VERSION 5.8 ;
BUSBITCHARS "[]" ;
DIVIDERCHAR "/" ;
UNITS
    DATABASE MICRONS 1000 ;
END UNITS

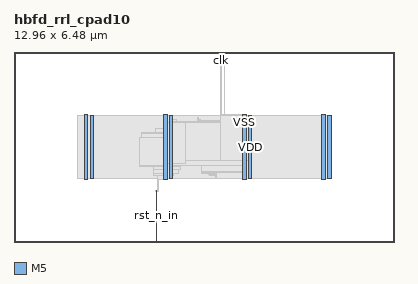
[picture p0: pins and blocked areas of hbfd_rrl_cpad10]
MACRO hbfd_rrl_cpad10
  FOREIGN hbfd_rrl_cpad10 0 0 ;
  CLASS BLOCK ;
  SIZE 12.96 BY 6.48 ;
  PIN clk
    DIRECTION INPUT ;
    USE SIGNAL ;
    PORT
      LAYER M5 ;
        RECT  7.056 6.396 7.08 6.48 ;
    END
  END clk
  PIN rst_n
    DIRECTION OUTPUT ;
    USE SIGNAL ;
    PORT
      LAYER M5 ;
        RECT  7.152 6.396 7.176 6.48 ;
    END
  END rst_n
  PIN rst_n_in
    DIRECTION INPUT ;
    USE SIGNAL ;
    PORT
      LAYER M5 ;
        RECT  4.848 0 4.872 0.084 ;
    END
    PORT
      LAYER M5 ;
        RECT  4.848 0.016 4.872 1.763 ;
    END
  END rst_n_in
  PIN VDD
    DIRECTION INOUT ;
    USE POWER ;
    PORT
      LAYER M5 ;
        RECT  10.692 2.151 10.812 4.329 ;
        RECT  7.992 2.151 8.112 4.329 ;
        RECT  5.292 2.151 5.412 4.329 ;
        RECT  2.592 2.151 2.712 4.329 ;
    END
  END VDD
  PIN VSS
    DIRECTION INOUT ;
    USE GROUND ;
    PORT
      LAYER M5 ;
        RECT  10.5 2.137 10.62 4.343 ;
        RECT  7.8 2.137 7.92 4.343 ;
        RECT  5.1 2.137 5.22 4.343 ;
        RECT  2.4 2.137 2.52 4.343 ;
    END
  END VSS
  # OT_OBS_CLOSED layer=M5 d_um=1.536 added=1
  OBS
    LAYER RVTN ;
     RECT  2.16 2.16 10.8 2.295 ;
     RECT  2.16 2.565 10.8 2.835 ;
     RECT  2.16 3.105 10.8 3.375 ;
     RECT  2.16 3.645 10.8 3.915 ;
     RECT  2.16 4.185 10.8 4.32 ;
    LAYER RVTP ;
     RECT  2.16 2.295 10.8 2.565 ;
     RECT  2.16 2.835 10.8 3.105 ;
     RECT  2.16 3.375 10.8 3.645 ;
     RECT  2.16 3.915 10.8 4.185 ;
    LAYER M1 ;
     RECT  2.16 2.151 10.8 4.329 ;
    LAYER M2 ;
     RECT  2.16 2.151 10.8 4.329 ;
     RECT  10.8 2.421 10.812 4.059 ;
    LAYER M3 ;
     RECT  4.896 1.723 4.914 2.143 ;
     RECT  4.896 2.143 5.205 2.263 ;
     RECT  6.876 2.191 6.894 2.263 ;
     RECT  6.66 2.263 6.894 2.299 ;
     RECT  4.752 2.263 5.454 2.335 ;
     RECT  6.624 2.299 6.894 2.335 ;
     RECT  6.408 2.335 6.894 2.371 ;
     RECT  7.815 2.143 7.905 2.371 ;
     RECT  2.415 2.143 2.505 2.413 ;
     RECT  6.408 2.371 7.905 2.413 ;
     RECT  10.515 2.143 10.605 2.413 ;
     RECT  4.752 2.335 5.598 2.461 ;
     RECT  4.752 2.461 5.67 2.569 ;
     RECT  4.284 2.569 5.67 2.605 ;
     RECT  6.408 2.413 8.097 2.605 ;
     RECT  4.284 2.605 8.097 3.569 ;
     RECT  4.356 3.569 8.097 3.725 ;
     RECT  4.824 3.725 8.097 3.875 ;
     RECT  2.415 2.413 2.697 4.067 ;
     RECT  5.115 3.875 8.097 4.067 ;
     RECT  10.515 2.413 10.797 4.067 ;
     RECT  5.115 4.067 7.905 4.109 ;
     RECT  6.264 4.109 7.905 4.145 ;
     RECT  5.115 4.109 5.526 4.181 ;
     RECT  6.264 4.145 6.354 4.181 ;
     RECT  6.264 4.181 6.282 4.253 ;
     RECT  2.415 4.067 2.505 4.337 ;
     RECT  5.115 4.181 5.205 4.337 ;
     RECT  7.164 4.145 7.905 4.337 ;
     RECT  10.515 4.067 10.605 4.337 ;
     RECT  7.164 4.337 7.182 6.365 ;
    LAYER M4 ;
     RECT  2.408 2.148 2.512 4.332 ;
     RECT  2.512 2.418 2.704 4.062 ;
     RECT  4.837 1.728 4.925 1.752 ;
     RECT  4.345 3.696 5.108 3.72 ;
     RECT  5.108 2.148 5.212 4.332 ;
     RECT  5.212 2.418 5.404 4.062 ;
     RECT  5.404 2.688 5.843 4.056 ;
     RECT  5.843 2.784 6.473 4.056 ;
     RECT  6.473 2.784 6.545 3.624 ;
     RECT  7.109 6.336 7.193 6.36 ;
     RECT  6.545 2.784 7.808 3.432 ;
     RECT  7.808 2.148 7.912 4.332 ;
     RECT  7.912 2.418 8.104 4.062 ;
     RECT  10.508 2.148 10.612 4.332 ;
     RECT  10.612 2.418 10.804 4.062 ;
    LAYER M5 ;
     RECT  2.4 2.137 2.52 2.151 ;
     RECT  5.1 2.137 5.22 2.151 ;
     RECT  7.8 2.137 7.92 2.151 ;
     RECT  10.5 2.137 10.62 2.151 ;
     RECT  5.1 2.151 5.412 2.677 ;
     RECT  7.8 2.151 8.112 2.773 ;
     RECT  5.1 2.677 5.832 4.067 ;
     RECT  2.4 2.151 2.712 4.329 ;
     RECT  5.1 4.067 5.412 4.329 ;
     RECT  7.056 2.773 8.112 4.329 ;
     RECT  10.5 2.151 10.812 4.329 ;
     RECT  2.4 4.329 2.52 4.343 ;
     RECT  5.1 4.329 5.22 4.343 ;
     RECT  7.056 4.329 7.92 4.343 ;
     RECT  10.5 4.329 10.62 4.343 ;
     RECT  7.056 4.343 7.08 6.325 ;
     RECT  7.056 6.325 7.176 6.396 ;
     RECT  7.08 6.396 7.152 6.416 ;
     RECT  5.832 2.773 7.056 4.067 ;
  END
END hbfd_rrl_cpad10
END LIBRARY
